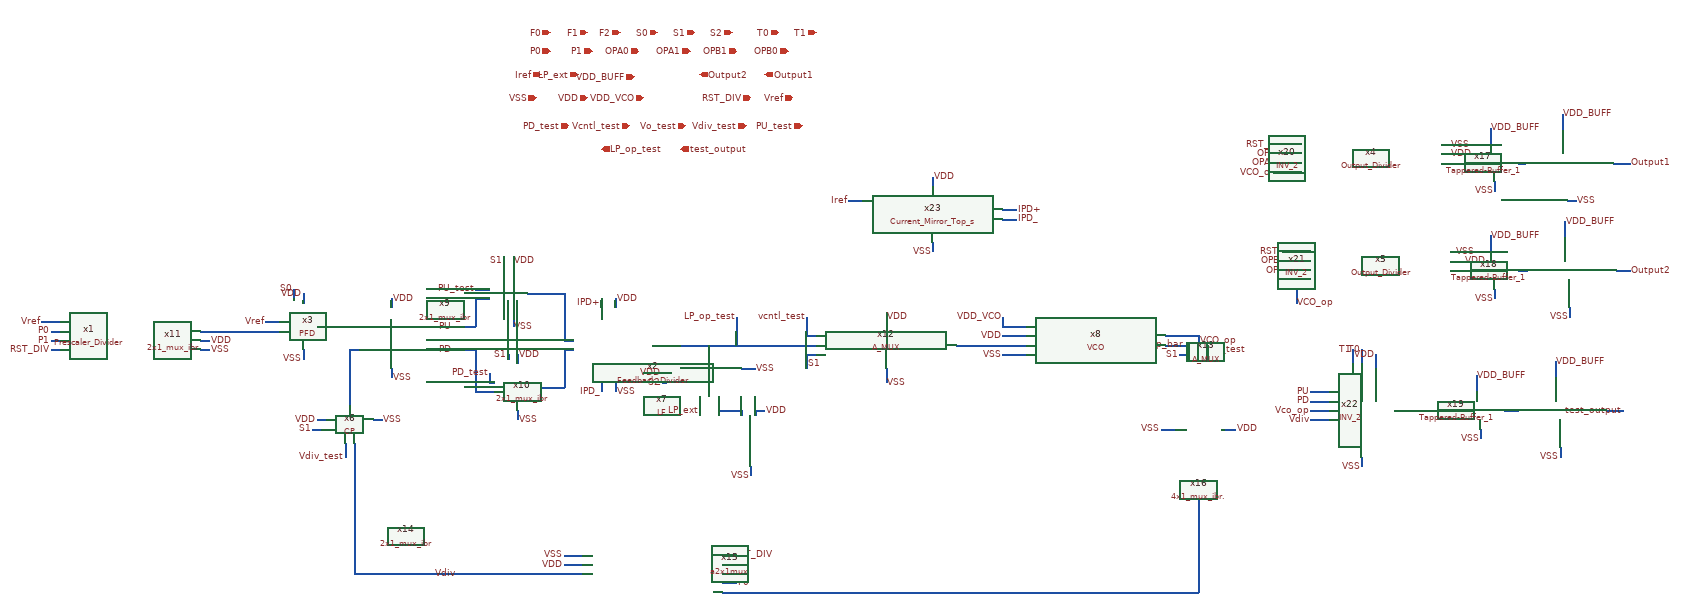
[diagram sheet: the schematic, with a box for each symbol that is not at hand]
v {xschem version=3.1.0 file_version=1.2
}
G {}
K {}
V {}
S {}
E {}
N 310 -950 330 -950 {
lab=P0}
N 310 -930 330 -930 {
lab=P1}
N 310 -910 330 -910 {
lab=RST_DIV}
N 630 -910 650 -910 {
lab=VSS}
N 630 -930 650 -930 {
lab=VDD}
N 1040 -1020 1040 -1000 {
lab=VDD}
N 1040 -870 1040 -850 {
lab=VSS}
N 950 -960 970 -960 {
lab=#net1}
N 950 -910 970 -910 {
lab=#net2}
N 1110 -910 1130 -910 {
lab=PD}
N 1130 -960 1220 -960 {
lab=PU}
N 1130 -910 1220 -910 {
lab=PD}
N 1160 -430 1450 -430 {
lab=Vdiv}
N 2350 -960 2390 -960 {
lab=VDD_VCO}
N 1110 -960 1130 -960 {
lab=PU}
N 2350 -980 2350 -960 {
lab=VDD_VCO}
N 1410 -470 1450 -470 {
lab=VSS}
N 1410 -450 1450 -450 {
lab=VDD}
N 1750 -450 1780 -450 {
lab=F2}
N 1750 -470 1780 -470 {
lab=RST_DIV}
N 2390 -960 2400 -960 {
lab=VDD_VCO}
N 1750 -410 1780 -410 {
lab=F0}
N 1750 -430 1780 -430 {
lab=F1}
N 2960 -1350 2990 -1350 {
lab=RST_DIV}
N 2930 -1290 2990 -1290 {
lab=VCO_op}
N 2950 -1330 2990 -1330 {
lab=OPA1}
N 2940 -1310 2990 -1310 {
lab=OPA0}
N 3290 -1350 3310 -1350 {
lab=VSS}
N 3290 -1330 3310 -1330 {
lab=VDD}
N 3290 -1310 3330 -1310 {
lab=#net3}
N 2980 -1060 3010 -1060 {
lab=VCO_op}
N 2980 -1060 2980 -1010 {
lab=VCO_op}
N 2950 -1120 3010 -1120 {
lab=RST_DIV}
N 2970 -1080 3010 -1080 {
lab=OPB0}
N 2960 -1100 3010 -1100 {
lab=OPB1}
N 3310 -1120 3330 -1120 {
lab=VSS}
N 3310 -1080 3330 -1080 {
lab=#net4}
N 3310 -1100 3350 -1100 {
lab=VDD}
N 1520 -1020 1520 -1000 {
lab=VDD}
N 1520 -840 1520 -820 {
lab=VSS}
N 1410 -930 1430 -930 {
lab=#net5}
N 1410 -910 1430 -910 {
lab=#net6}
N 1490 -1020 1490 -1000 {
lab=IPD+}
N 1490 -840 1490 -820 {
lab=IPD_}
N 720 -950 750 -950 {
lab=#net7}
N 290 -970 320 -970 {
lab=Vref}
N 630 -950 700 -950 {
lab=#net7}
N 700 -950 720 -950 {
lab=#net7}
N 320 -970 330 -970 {
lab=Vref}
N 1220 -910 1220 -820 {
lab=PD}
N 1220 -820 1260 -820 {
lab=PD}
N 1250 -840 1260 -840 {
lab=PD_test}
N 1250 -860 1250 -840 {
lab=PD_test}
N 1220 -1020 1220 -960 {
lab=PU}
N 1220 -1020 1250 -1020 {
lab=PU}
N 1300 -980 1300 -960 {
lab=VSS}
N 1290 -900 1290 -890 {
lab=S1}
N 1310 -900 1310 -880 {
lab=VDD}
N 1330 -1030 1410 -1030 {
lab=#net5}
N 1410 -1030 1410 -960 {
lab=#net5}
N 1410 -910 1410 -830 {
lab=#net6}
N 1340 -830 1410 -830 {
lab=#net6}
N 1410 -960 1410 -930 {
lab=#net5}
N 1280 -1110 1280 -1090 {
lab=S1}
N 1300 -1110 1300 -1080 {
lab=VDD}
N 1220 -1040 1250 -1040 {
lab=PU_test}
N 1310 -780 1310 -760 {
lab=VSS}
N 850 -910 850 -890 {
lab=VSS}
N 850 -1030 850 -1010 {
lab=VDD}
N 830 -1040 830 -1020 {
lab=S0}
N 750 -950 800 -950 {
lab=#net7}
N 770 -970 800 -970 {
lab=Vref}
N 2100 -990 2100 -970 {
lab=VDD}
N 2100 -870 2100 -840 {
lab=VSS}
N 1930 -940 1950 -940 {
lab=vcntl_test}
N 1930 -980 1930 -940 {
lab=vcntl_test}
N 1930 -900 1950 -900 {
lab=S1}
N 1930 -900 1930 -870 {
lab=S1}
N 2790 -920 2790 -900 {
lab=Vo_test}
N 2770 -410 2770 -400 {
lab=#net8}
N 2690 -740 2720 -740 {
lab=VSS}
N 2820 -740 2850 -740 {
lab=VDD}
N 2730 -900 2750 -900 {
lab=S1}
N 2770 -400 2770 -390 {
lab=#net8}
N 2420 -390 2770 -390 {
lab=#net8}
N 1750 -390 2420 -390 {
lab=#net8}
N 2250 -920 2400 -920 {
lab=#net9}
N 2350 -940 2400 -940 {
lab=VDD}
N 2350 -900 2400 -900 {
lab=VSS}
N 2700 -940 2770 -940 {
lab=VCO_op}
N 2700 -920 2750 -920 {
lab=VCO_op_bar}
N 2770 -940 2770 -900 {
lab=VCO_op}
N 880 -960 940 -960 {
lab=#net1}
N 1000 -760 1020 -760 {
lab=VSS}
N 880 -760 900 -760 {
lab=VDD}
N 870 -740 890 -740 {
lab=S1}
N 960 -710 960 -660 {
lab=Vdiv}
N 940 -710 940 -680 {
lab=Vdiv_test}
N 950 -850 950 -790 {
lab=#net2}
N 960 -660 960 -610 {
lab=Vdiv}
N 950 -910 950 -850 {
lab=#net2}
N 940 -960 950 -960 {
lab=#net1}
N 1810 -660 1810 -640 {
lab=VSS}
N 1820 -780 1820 -770 {
lab=VDD}
N 1820 -780 1840 -780 {
lab=VDD}
N 1620 -860 1640 -860 {
lab=VDD}
N 1790 -870 1820 -870 {
lab=VSS}
N 1700 -810 1700 -780 {
lab=LP_ext}
N 1790 -780 1790 -770 {
lab=#net10}
N 1740 -780 1790 -780 {
lab=#net10}
N 1740 -810 1740 -780 {
lab=#net10}
N 1720 -920 1720 -910 {
lab=LP_op_test}
N 960 -430 1160 -430 {
lab=Vdiv}
N 960 -610 960 -490 {
lab=Vdiv}
N 2770 -530 2770 -410 {
lab=#net8}
N 1620 -840 1630 -840 {
lab=S2}
N 1600 -920 1950 -920 {
lab=LP_op_test}
N 3010 -820 3050 -820 {
lab=PU}
N 3010 -800 3050 -800 {
lab=PD}
N 3010 -780 3050 -780 {
lab=Vco_op}
N 3010 -760 3050 -760 {
lab=Vdiv}
N 1780 -980 1780 -920 {
lab=LP_op_test}
N 3150 -900 3150 -870 {
lab=VDD}
N 3120 -910 3120 -880 {
lab=T0}
N 3100 -910 3100 -880 {
lab=T1}
N 3120 -680 3120 -660 {
lab=VSS}
N 3190 -780 3220 -780 {
lab=#net11}
N 3660 -1310 3695 -1310 {
lab=Output1}
N 3645 -780 3680 -780 {
lab=test_output}
N 3665 -1080 3695 -1080 {
lab=Output2}
N 3330 -1310 3355 -1310 {
lab=#net3}
N 3455 -1080 3475 -1080 {
lab=#net14}
N 3330 -1080 3355 -1080 {
lab=#net4}
N 3425 -780 3455 -780 {
lab=#net13}
N 3220 -780 3325 -780 {
lab=#net11}
N 3550 -1410 3550 -1380 {
lab=VDD_BUFF}
N 3550 -1415 3550 -1410 {
lab=VDD_BUFF}
N 3555 -1180 3555 -1150 {
lab=VDD_BUFF}
N 3555 -1185 3555 -1180 {
lab=VDD_BUFF}
N 3535 -880 3535 -850 {
lab=VDD_BUFF}
N 3535 -885 3535 -880 {
lab=VDD_BUFF}
N 3365 -850 3365 -820 {
lab=VDD_BUFF}
N 3365 -855 3365 -850 {
lab=VDD_BUFF}
N 3395 -1150 3395 -1120 {
lab=VDD_BUFF}
N 3395 -1155 3395 -1150 {
lab=VDD_BUFF}
N 3395 -1380 3395 -1350 {
lab=VDD_BUFF}
N 3395 -1385 3395 -1380 {
lab=VDD_BUFF}
N 3405 -1270 3405 -1250 {
lab=VSS}
N 3405 -1040 3405 -1020 {
lab=VSS}
N 3375 -740 3375 -720 {
lab=VSS}
N 3545 -700 3545 -680 {
lab=VSS}
N 3565 -1000 3565 -980 {
lab=VSS}
N 3560 -1230 3580 -1230 {
lab=VSS}
N 2200 -1280 2200 -1260 {
lab=VDD}
N 2350 -1210 2380 -1210 {
lab=#net15}
N 2350 -1190 2380 -1190 {
lab=#net16}
N 2020 -1230 2050 -1230 {
lab=#net17}
N 2770 -590 2770 -530 {}
N 960 -490 960 -430 {}
N 2200 -1140 2200 -1120 {}
N 2750 -900 2750 -890 {}
N 2770 -900 2770 -890 {}
N 2790 -900 2790 -890 {}
N 3455 -1310 3470 -1310 {}
C {devices/ipin.sym} 1690 -1590 0 0 {name=p45 lab=S1}
C {devices/ipin.sym} 1610 -1590 0 0 {name=p46 lab=S0}
C {devices/ipin.sym} 1870 -1590 0 0 {name=p47 lab=T0}
C {devices/ipin.sym} 1950 -1590 0 0 {name=p48 lab=T1}
C {devices/iopin.sym} 1460 -1450 0 0 {name=p58 lab=VDD}
C {devices/iopin.sym} 1580 -1450 0 0 {name=p59 lab=VDD_VCO}
C {devices/ipin.sym} 1900 -1450 0 0 {name=p60 lab=Vref}
C {devices/ipin.sym} 1460 -1590 0 0 {name=p62 lab=F1}
C {devices/ipin.sym} 1530 -1590 0 0 {name=p63 lab=F2}
C {devices/ipin.sym} 1380 -1550 0 0 {name=p64 lab=P0}
C {devices/ipin.sym} 1470 -1550 0 0 {name=p65 lab=P1}
C {devices/ipin.sym} 1570 -1550 0 0 {name=p66 lab=OPA0}
C {devices/ipin.sym} 1810 -1450 0 0 {name=p67 lab=RST_DIV}
C {devices/ipin.sym} 1380 -1590 0 0 {name=p68 lab=F0}
C {devices/ipin.sym} 1680 -1550 0 0 {name=p69 lab=OPA1}
C {devices/ipin.sym} 1780 -1550 0 0 {name=p70 lab=OPB1}
C {devices/ipin.sym} 1890 -1550 0 0 {name=p71 lab=OPB0}
C {devices/ipin.sym} 1800 -1390 0 0 {name=p72 lab=Vdiv_test}
C {devices/ipin.sym} 1920 -1390 0 0 {name=p73 lab=PU_test}
C {devices/ipin.sym} 1420 -1390 0 0 {name=p74 lab=PD_test}
C {devices/ipin.sym} 1550 -1390 0 0 {name=p75 lab=Vcntl_test}
C {devices/ipin.sym} 1670 -1390 0 0 {name=p76 lab=Vo_test}
C {devices/opin.sym} 1490 -1340 0 0 {name=p77 lab=LP_op_test}
C {devices/opin.sym} 1660 -1340 0 0 {name=p78 lab=test_output}
C {devices/opin.sym} 1700 -1500 0 0 {name=p79 lab=Output2}
C {devices/opin.sym} 1840 -1500 0 0 {name=p80 lab=Output1}
C {devices/iopin.sym} 1350 -1450 0 0 {name=p57 lab=VSS}
C {devices/lab_pin.sym} 310 -930 0 0 {name=p139 sig_type=std_logic lab=P1}
C {devices/lab_pin.sym} 310 -950 0 0 {name=p140 sig_type=std_logic lab=P0}
C {devices/lab_pin.sym} 290 -970 0 0 {name=p141 sig_type=std_logic lab=Vref
}
C {devices/lab_pin.sym} 650 -910 2 0 {name=p142 sig_type=std_logic lab=VSS}
C {devices/lab_pin.sym} 650 -930 2 0 {name=p143 sig_type=std_logic lab=VDD}
C {devices/lab_pin.sym} 310 -910 0 0 {name=p144 sig_type=std_logic lab=RST_DIV}
C {PFD.sym} 750 -750 0 0 {name=x3}
C {devices/lab_pin.sym} 1040 -1020 2 0 {name=p9 sig_type=std_logic lab=VDD}
C {devices/lab_wire.sym} 1040 -850 2 0 {name=p10 sig_type=std_logic lab=VSS}
C {devices/lab_pin.sym} 1180 -430 1 0 {name=p28 sig_type=std_logic lab=Vdiv
}
C {devices/lab_pin.sym} 2350 -980 0 0 {name=p12 sig_type=std_logic lab=VDD_VCO}
C {devices/lab_pin.sym} 2740 -920 1 0 {name=p13 sig_type=std_logic lab=VCO_op_bar
}
C {devices/lab_pin.sym} 1410 -450 0 0 {name=p14 sig_type=std_logic lab=VDD}
C {devices/lab_wire.sym} 1410 -470 1 0 {name=p15 sig_type=std_logic lab=VSS}
C {devices/lab_pin.sym} 1780 -980 1 0 {name=p19 sig_type=std_logic lab=LP_op_test
}
C {devices/lab_pin.sym} 1170 -960 1 0 {name=p20 sig_type=std_logic lab=PU}
C {devices/lab_pin.sym} 1170 -910 1 0 {name=p21 sig_type=std_logic lab=PD}
C {Feedback_Divider.sym} 1600 -430 0 1 {name=x2}
C {devices/lab_pin.sym} 1780 -410 2 0 {name=p22 sig_type=std_logic lab=F0}
C {devices/lab_pin.sym} 1780 -430 2 0 {name=p23 sig_type=std_logic lab=F1}
C {devices/lab_pin.sym} 1780 -450 2 0 {name=p24 sig_type=std_logic lab=F2}
C {devices/lab_pin.sym} 3310 -1330 2 0 {name=p32 sig_type=std_logic lab=VDD}
C {devices/lab_pin.sym} 3310 -1350 2 0 {name=p33 sig_type=std_logic lab=VSS}
C {devices/lab_wire.sym} 2940 -1310 0 0 {name=p82 sig_type=std_logic lab=OPA0}
C {devices/lab_wire.sym} 2950 -1330 0 0 {name=p83 sig_type=std_logic lab=OPA1}
C {devices/lab_pin.sym} 2960 -1350 1 0 {name=p34 sig_type=std_logic lab=RST_DIV}
C {devices/lab_pin.sym} 3340 -1100 0 1 {name=p85 sig_type=std_logic lab=VDD}
C {devices/lab_pin.sym} 3320 -1120 0 1 {name=p86 sig_type=std_logic lab=VSS}
C {devices/lab_wire.sym} 2960 -1100 2 1 {name=p87 sig_type=std_logic lab=OPB1}
C {devices/lab_wire.sym} 2970 -1080 2 1 {name=p88 sig_type=std_logic lab=OPB0}
C {devices/lab_pin.sym} 3695 -1080 0 1 {name=p90 sig_type=std_logic lab=Output2}
C {Output_Divider.sym} 3160 -1090 0 0 {name=x5}
C {devices/lab_pin.sym} 2990 -1120 1 0 {name=p35 sig_type=std_logic lab=RST_DIV}
C {devices/lab_pin.sym} 2980 -1010 2 0 {name=p37 sig_type=std_logic lab=VCO_op
}
C {devices/lab_pin.sym} 2940 -1290 2 1 {name=p40 sig_type=std_logic lab=VCO_op
}
C {devices/lab_pin.sym} 1770 -470 2 0 {name=p39 sig_type=std_logic lab=RST_DIV}
C {devices/lab_wire.sym} 1520 -820 2 0 {name=p1 sig_type=std_logic lab=VSS}
C {devices/lab_pin.sym} 1520 -1020 2 0 {name=p50 sig_type=std_logic lab=VDD}
C {CP.sym} 940 -720 0 0 {name=x6}
C {devices/lab_wire.sym} 1490 -1010 0 0 {name=p52 sig_type=std_logic lab=IPD+}
C {devices/lab_wire.sym} 1490 -820 0 0 {name=p53 sig_type=std_logic lab=IPD_}
C {Output_Divider.sym} 3140 -1320 0 0 {name=x4}
C {devices/lab_pin.sym} 1220 -1040 0 0 {name=p2 sig_type=std_logic lab=PU_test
}
C {devices/lab_pin.sym} 1250 -860 1 0 {name=p3 sig_type=std_logic lab=PD_test
}
C {devices/lab_pin.sym} 1300 -1100 2 0 {name=p4 sig_type=std_logic lab=VDD}
C {devices/lab_pin.sym} 1310 -900 2 0 {name=p5 sig_type=std_logic lab=VDD}
C {devices/lab_wire.sym} 1310 -760 2 0 {name=p6 sig_type=std_logic lab=VSS}
C {devices/lab_wire.sym} 1300 -960 2 0 {name=p7 sig_type=std_logic lab=VSS}
C {devices/lab_pin.sym} 1280 -1100 1 0 {name=p106 sig_type=std_logic lab=S1}
C {devices/lab_pin.sym} 1290 -900 1 0 {name=p8 sig_type=std_logic lab=S1}
C {devices/lab_wire.sym} 850 -890 3 0 {name=p11 sig_type=std_logic lab=VSS}
C {devices/lab_pin.sym} 850 -1030 3 1 {name=p16 sig_type=std_logic lab=VDD}
C {devices/lab_pin.sym} 830 -1040 1 0 {name=p17 sig_type=std_logic lab=S0}
C {devices/lab_pin.sym} 770 -970 1 0 {name=p18 sig_type=std_logic lab=Vref
}
C {A_MUX.sym} 2100 -920 0 0 {name=x12}
C {devices/lab_pin.sym} 2100 -980 2 0 {name=p25 sig_type=std_logic lab=VDD}
C {devices/lab_wire.sym} 2100 -840 2 0 {name=p26 sig_type=std_logic lab=VSS}
C {devices/lab_pin.sym} 1930 -880 2 0 {name=p27 sig_type=std_logic lab=S1}
C {devices/lab_pin.sym} 1930 -980 0 0 {name=p29 sig_type=std_logic lab=vcntl_test
}
C {devices/lab_pin.sym} 2770 -930 2 0 {name=p30 sig_type=std_logic lab=VCO_op
}
C {devices/lab_pin.sym} 2790 -910 2 0 {name=p31 sig_type=std_logic lab=Vo_test
}
C {A_MUX.sym} 2770 -740 1 0 {name=x13}
C {devices/lab_pin.sym} 2730 -900 0 0 {name=p36 sig_type=std_logic lab=S1}
C {devices/lab_wire.sym} 2690 -740 0 0 {name=p38 sig_type=std_logic lab=VSS}
C {devices/lab_pin.sym} 2850 -740 2 0 {name=p41 sig_type=std_logic lab=VDD}
C {devices/lab_pin.sym} 2350 -940 0 0 {name=p42 sig_type=std_logic lab=VDD}
C {devices/lab_wire.sym} 2350 -900 2 1 {name=p89 sig_type=std_logic lab=VSS}
C {devices/lab_wire.sym} 1020 -760 2 0 {name=p91 sig_type=std_logic lab=VSS}
C {devices/lab_pin.sym} 880 -760 2 1 {name=p92 sig_type=std_logic lab=VDD}
C {devices/lab_pin.sym} 870 -740 0 0 {name=p93 sig_type=std_logic lab=S1}
C {devices/lab_pin.sym} 940 -680 0 0 {name=p94 sig_type=std_logic lab=Vdiv_test

}
C {devices/lab_wire.sym} 1810 -640 2 1 {name=p43 sig_type=std_logic lab=VSS}
C {devices/lab_wire.sym} 1840 -780 0 1 {name=p98 sig_type=std_logic lab=VDD}
C {devices/lab_wire.sym} 1820 -870 2 0 {name=p99 sig_type=std_logic lab=VSS}
C {devices/lab_wire.sym} 1620 -860 2 1 {name=p100 sig_type=std_logic lab=VDD}
C {devices/lab_wire.sym} 1620 -840 1 1 {name=p44 sig_type=std_logic lab=S2}
C {LF.sym} 1950 -610 0 1 {name=x7}
C {a2x1mux.sym} 1880 -490 3 0 {name=x15}
C {4x1_mux_ibr..sym} 2770 -670 0 0 {name=x16}
C {devices/lab_pin.sym} 3010 -820 0 0 {name=p97 sig_type=std_logic lab=PU}
C {devices/lab_pin.sym} 3010 -800 0 0 {name=p54 sig_type=std_logic lab=PD}
C {devices/lab_pin.sym} 3010 -780 0 0 {name=p55 sig_type=std_logic lab=Vco_op
}
C {devices/lab_pin.sym} 3010 -760 0 0 {name=p105 sig_type=std_logic lab=Vdiv
}
C {devices/lab_pin.sym} 3100 -910 1 0 {name=p107 sig_type=std_logic lab=T1}
C {devices/lab_pin.sym} 3120 -910 1 0 {name=p108 sig_type=std_logic lab=T0}
C {devices/lab_pin.sym} 3150 -900 3 1 {name=p109 sig_type=std_logic lab=VDD}
C {devices/lab_wire.sym} 3120 -660 3 0 {name=p110 sig_type=std_logic lab=VSS}
C {devices/lab_pin.sym} 3680 -780 1 1 {name=p111 sig_type=std_logic lab=test_output}
C {devices/ipin.sym} 1770 -1590 0 0 {name=p56 lab=S2}
C {Prescaler_Divider.sym} 480 -940 2 1 {name=x1}
C {devices/iopin.sym} 1360 -1500 0 0 {name=p49 lab=Iref}
C {devices/lab_pin.sym} 1700 -780 0 0 {name=p51 sig_type=std_logic lab=LP_ext

}
C {devices/iopin.sym} 1440 -1500 0 0 {name=p81 lab=LP_ext}
C {2x1_mux_ibr.sym} 600 -840 0 0 {name=x11}
C {2x1_mux_ibr.sym} 1070 -510 3 0 {name=x14}
C {2x1_mux_ibr.sym} 1050 -910 0 0 {name=x9}
C {2x1_mux_ibr.sym} 1060 -710 0 0 {name=x10}
C {VCO.sym} 2550 -930 0 0 {name=x8}
C {Tappered-Buffer_1.sym} 3230 -1290 0 0 {name=x17}
C {Tappered-Buffer_1.sym} 3235 -1060 0 0 {name=x18}
C {Tappered-Buffer_1.sym} 3215 -760 0 0 {name=x19}
C {devices/lab_pin.sym} 3695 -1310 2 0 {name=p95 sig_type=std_logic lab=Output1}
C {INV_2.sym} 3075 -1270 0 0 {name=x20}
C {INV_2.sym} 3075 -1040 0 0 {name=x21}
C {INV_2.sym} 3045 -740 0 0 {name=x22}
C {devices/iopin.sym} 1560 -1495 0 0 {name=p84 lab=VDD_BUFF}
C {devices/lab_pin.sym} 3550 -1415 2 0 {name=p96 sig_type=std_logic lab=VDD_BUFF}
C {devices/lab_pin.sym} 3555 -1185 2 0 {name=p101 sig_type=std_logic lab=VDD_BUFF}
C {devices/lab_pin.sym} 3535 -885 2 0 {name=p102 sig_type=std_logic lab=VDD_BUFF}
C {devices/lab_pin.sym} 3365 -855 2 0 {name=p103 sig_type=std_logic lab=VDD_BUFF}
C {devices/lab_pin.sym} 3395 -1155 2 0 {name=p104 sig_type=std_logic lab=VDD_BUFF}
C {devices/lab_pin.sym} 3395 -1385 2 0 {name=p112 sig_type=std_logic lab=VDD_BUFF}
C {devices/lab_pin.sym} 3405 -1250 3 0 {name=p113 sig_type=std_logic lab=VSS}
C {devices/lab_pin.sym} 3405 -1020 3 0 {name=p114 sig_type=std_logic lab=VSS}
C {devices/lab_pin.sym} 3375 -720 3 0 {name=p115 sig_type=std_logic lab=VSS}
C {devices/lab_pin.sym} 3545 -680 3 0 {name=p116 sig_type=std_logic lab=VSS}
C {devices/lab_pin.sym} 3565 -980 3 0 {name=p117 sig_type=std_logic lab=VSS}
C {devices/lab_pin.sym} 3580 -1230 2 0 {name=p118 sig_type=std_logic lab=VSS}
C {Current_Mirror_Top_s.sym} 2200 -1200 0 0 {name=x23}
C {devices/lab_wire.sym} 2200 -1120 3 0 {name=p119 sig_type=std_logic lab=VSS}
C {devices/lab_pin.sym} 2200 -1280 2 0 {name=p120 sig_type=std_logic lab=VDD}
C {devices/lab_wire.sym} 2380 -1210 2 0 {name=p121 sig_type=std_logic lab=IPD+}
C {devices/lab_wire.sym} 2380 -1190 2 0 {name=p122 sig_type=std_logic lab=IPD_}
C {devices/lab_pin.sym} 2020 -1230 0 0 {name=p123 sig_type=std_logic lab=Iref}
